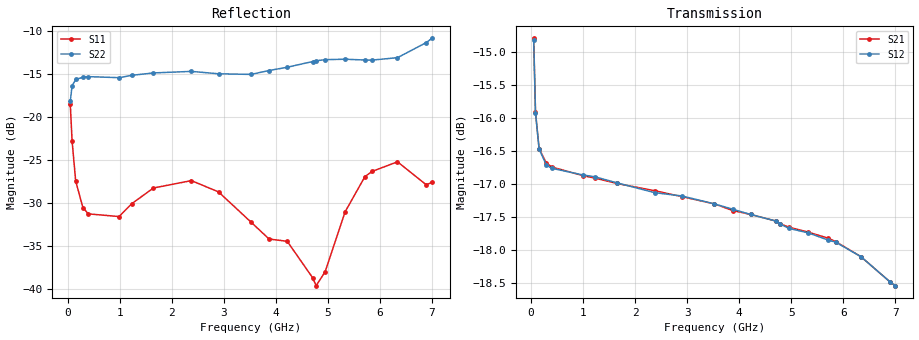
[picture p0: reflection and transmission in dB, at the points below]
! Integrated Device Technology
! Corporate Headquarters
! 6024 Silver Creek Valley Road
! San Jose, CA 95138  USA
! Phone:  1-408-284-8200
! Toll Free:  1-800-223-1366
! Webpage:  http://www.idt.com/
! Timing and RF Division
! 515 Groton Road, Suite 102
! Westford, MA 01886-6024
! Device:  F2258
! Description: Voltage Variable RF Attenuator
! Frequency:  50.0 -  6000.00 MHz
! Package:  3x3 mm Thin QFN Plastic Package: 16 pin
! Ports:  2 RF, 2 DC
!  Pin  1  = NC
!  Pin  2  = NC
!  Pin  3  = RF2  = Port 2
!  Pin  4  = GND
!  Pin  5  = Vdd
!  Pin  6  = NC
!  Pin  7  = VCTRL
!  Pin  8  = NC
!  Pin  9  = GND
!  Pin 10  = RF1  = Port 1
!  Pin 11  = NC
!  Pin 12  = NC
!  Pin 13  = NC
!  Pin 14  = NC
!  Pin 15  = NC
!  Pin 16  = NC
! Vcntrl:  1.230 Volts
! Vdd:  +3.300 Volts
! Current:  1.165 mA
! Data:  The device was measured on a the F2258 evaluation board which has
!  individual transmission lines to the RF pins.  Data was collected
!  using a calibrated network analyzer.  The evaluation board was
!  de-embedded using a TRL calibration technique.
!  The reference plane is the edge of the package pin.
! Misc:  SN 10
!  Action Tracker AT0285
! Date Measured:  2014-12-10
! Date:  2016-01-13  MJV
! Note:
!  Integrated Device Technology supplies this data as a sample of measured
!  data at the package pin for this product.  Your particular data for this
!  product may vary.
!  Data was taken at 25 degrees C.
!  Integrated Device Technology reserves the right to change this data at anytime.
!Freq_(GHz)  S11M_(dB)  S11P_(deg)  S21M_(dB)  S21P_(deg)  S12M_(dB)  S12P_(deg)  S22M_(dB)  S22P_(deg)
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# GHz S dB R 50
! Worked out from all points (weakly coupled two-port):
!   201 points, 50 MHz to 7 GHz, reference 50 ohm
!   highest |S21| = -14.79 dB at 50 MHz (marker M1); lowest = -18.5 dB at 7 GHz (marker M2)
!   lowest |S11| = -39.6 dB at 4.776 GHz (marker M3), VSWR 1.02, Z = 50.5 + j0.907 ohm
!   |S11| at or under -10 dB: start of sweep to end of sweep
!   |S22| runs from -18.2 to -10.9 dB; largest |S21 - S12| = 0.00066
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0.05  -18.51 -96.7  -14.79 -24.9  -14.81 -24.9  -18.20 -24.7
0.08475  -22.77 -84.1  -15.91 -17.7  -15.92 -17.7  -16.39 -12.5
0.15425  -27.44 -65.5  -16.46 -12.1  -16.47 -12.1  -15.66 -9.4
0.29325  -30.54 -41.2  -16.68 -9.9  -16.71 -9.9  -15.40 -10.5
0.3975  -31.25 -31.6  -16.74 -10.1  -16.76 -10.1  -15.33 -12.5
0.98825  -31.56 -19.5  -16.87 -16.5  -16.86 -16.5  -15.45 -27.7
1.2315  -30.07 -13.5  -16.91 -19.7  -16.89 -19.7  -15.18 -33.6
1.6485  -28.25 -7.6  -16.99 -25.4  -16.98 -25.4  -14.90 -43.3
2.37825  -27.39 6.3  -17.10 -35.4  -17.13 -35.4  -14.72 -60.1
2.8995  -28.70 21.4  -17.19 -42.7  -17.18 -42.7  -15.00 -74.5
3.525  -32.21 52.2  -17.30 -51.7  -17.30 -51.7  -15.07 -97.7
3.8725  -34.17 78.7  -17.40 -56.7  -17.38 -56.7  -14.62 -110.8
4.22  -34.43 92.2  -17.46 -61.6  -17.46 -61.6  -14.24 -120.9
4.7065  -38.64 69.5  -17.56 -68.4  -17.56 -68.4  -13.58 -131.1
4.776  -39.58 58.7  -17.60 -69.4  -17.60 -69.4  -13.49 -132.2
4.94975  -37.95 25.7  -17.65 -71.7  -17.67 -71.7  -13.36 -134.4
5.332  -31.02 0.0  -17.73 -77.0  -17.74 -76.9  -13.31 -139.1
5.71425  -26.92 -0.7  -17.82 -82.2  -17.85 -82.1  -13.40 -144.8
5.85325  -26.32 1.9  -17.87 -84.1  -17.88 -84.1  -13.41 -147.9
6.33975  -25.21 14.1  -18.10 -90.9  -18.10 -90.9  -13.13 -160.0
6.89575  -27.89 67.7  -18.48 -97.6  -18.48 -97.6  -11.37 -177.0
7  -27.58 85.9  -18.54 -98.5  -18.54 -98.6  -10.89 -179.8
